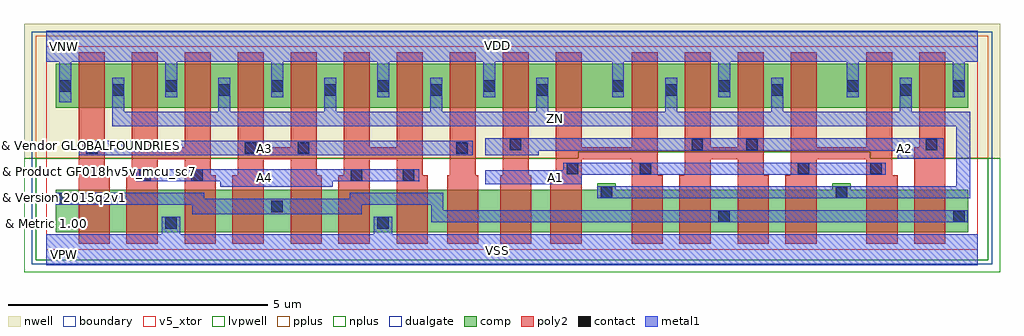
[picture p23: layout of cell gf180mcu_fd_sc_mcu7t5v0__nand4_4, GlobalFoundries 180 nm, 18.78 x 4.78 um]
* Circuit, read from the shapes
.subckt gf180mcu_fd_sc_mcu7t5v0__nand4_4 A1 A2 A3 A4 VDD VNW VSS ZN
XM1 n1 A3 n2 VSUBS nfet_05v0 w=0.82u l=0.6u
XM2 VSS A4 n1 VSUBS nfet_05v0 w=0.82u l=0.6u
XM3 n3 A4 VSS VSUBS nfet_05v0 w=0.82u l=0.6u
XM4 n2 A3 n3 VSUBS nfet_05v0 w=0.82u l=0.6u
XM5 n4 A3 n2 VSUBS nfet_05v0 w=0.82u l=0.6u
XM6 VSS A4 n4 VSUBS nfet_05v0 w=0.82u l=0.6u
XM7 n5 A4 VSS VSUBS nfet_05v0 w=0.82u l=0.6u
XM8 n6 A3 n5 VSUBS nfet_05v0 w=0.82u l=0.6u
XM9 n7 A2 n6 VSUBS nfet_05v0 w=0.82u l=0.6u
XM10 ZN A1 n7 VSUBS nfet_05v0 w=0.82u l=0.6u
XM11 n8 A1 ZN VSUBS nfet_05v0 w=0.82u l=0.6u
XM12 n2 A2 n8 VSUBS nfet_05v0 w=0.82u l=0.6u
XM13 n9 A2 n2 VSUBS nfet_05v0 w=0.82u l=0.6u
XM14 ZN A1 n9 VSUBS nfet_05v0 w=0.82u l=0.6u
XM15 n10 A1 ZN VSUBS nfet_05v0 w=0.82u l=0.6u
XM16 n2 A2 n10 VSUBS nfet_05v0 w=0.82u l=0.6u
XM17 ZN A3 VDD VNW pfet_05v0 w=0.845u l=0.5u m=4
XM18 VDD A4 ZN VNW pfet_05v0 w=0.845u l=0.5u m=4
XM19 ZN A2 VDD VNW pfet_05v0 w=0.845u l=0.5u m=4
XM20 VDD A1 ZN VNW pfet_05v0 w=0.845u l=0.5u m=4
.ends

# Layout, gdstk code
import gdstk
lib = gdstk.Library(unit=1e-6, precision=1e-09)
def R(c, l, rs):  # rectangles x0, y0, x1, y1
    for r in rs: c.add(gdstk.rectangle(r[:2], r[2:], *l))
def A(c, l, x, y, w, h, nx, ny, dx, dy):  # array of equal rectangles
    R(c, l, [(x+i*dx, y+j*dy, x+i*dx+w, y+j*dy+h) for i in range(nx) for j in range(ny)])
def P(c, l, *ps):  # polygons
    for p in ps: c.add(gdstk.Polygon(p, *l))
boundary = (0, 0)
nwell = (21, 0)
comp = (22, 0)
poly2 = (30, 0)
pplus = (31, 0)
nplus = (32, 0)
contact = (33, 0)
metal1 = (34, 0)
dualgate = (55, 0)
v5_xtor = (112, 1)
lvpwell = (204, 0)

gf180mcu_fd_sc_mcu7t5v0_ = lib.new_cell('gf180mcu_fd_sc_mcu7t5v0__nand4_4')
R(gf180mcu_fd_sc_mcu7t5v0_, boundary, [(0,0,17.92,3.92)])
P(gf180mcu_fd_sc_mcu7t5v0_, nwell, [(-0.43,1.76),(-0.43,4.35),(18.35,4.35),(18.35,1.76),(15.85,1.76),(15.85,1.885),(10.23,1.885),(10.23,1.76)])
R(gf180mcu_fd_sc_mcu7t5v0_, comp, [(0.18,2.735,17.74,3.58)])
P(gf180mcu_fd_sc_mcu7t5v0_, comp, [(0.18,0.34),(0.18,1.16),(10.6,1.16),(10.6,1.285),(10.96,1.285),(10.96,1.16),(15.12,1.16),(15.12,1.285),(15.48,1.285),(15.48,1.16),(17.74,1.16),(17.74,0.34)])
P(gf180mcu_fd_sc_mcu7t5v0_, poly2, [(0.62,0.12),(0.62,3.8),(1.12,3.8),(1.12,1.44),(1.22,1.44),(1.22,0.12)],
  [(1.54,0.12),(1.54,1.44),(1.64,1.44),(1.64,3.8),(2.14,3.8),(2.14,1.97),(2.66,1.97),(2.66,3.8),(3.16,3.8),(3.16,1.44),(3.26,1.44),(3.26,0.12),(2.66,0.12),(2.66,1.74),(2.14,1.74),(2.14,0.12)],
  [(3.58,0.12),(3.58,1.44),(3.68,1.44),(3.68,3.8),(4.18,3.8),(4.18,1.97),(4.7,1.97),(4.7,3.8),(5.2,3.8),(5.2,1.44),(5.3,1.44),(5.3,0.12),(4.7,0.12),(4.7,1.74),(4.18,1.74),(4.18,0.12)],
  [(5.62,0.12),(5.62,1.44),(5.72,1.44),(5.72,3.8),(6.22,3.8),(6.22,1.97),(6.74,1.97),(6.74,3.8),(7.24,3.8),(7.24,1.44),(7.34,1.44),(7.34,0.12),(6.74,0.12),(6.74,1.74),(6.22,1.74),(6.22,0.12)],
  [(7.71,0.12),(7.71,1.44),(7.76,1.44),(7.76,3.8),(8.26,3.8),(8.26,1.44),(8.31,1.44),(8.31,0.12)],
  [(8.73,0.12),(8.73,1.44),(8.78,1.44),(8.78,3.8),(9.28,3.8),(9.28,1.44),(9.33,1.44),(9.33,0.12)],
  [(9.7,0.12),(9.7,1.44),(9.8,1.44),(9.8,3.8),(10.3,3.8),(10.3,1.97),(11.26,1.97),(11.26,3.8),(11.76,3.8),(11.76,1.44),(11.86,1.44),(11.86,0.12),(11.26,0.12),(11.26,1.74),(10.3,1.74),(10.3,0.12)],
  [(12.18,0.12),(12.18,1.44),(12.28,1.44),(12.28,3.8),(12.78,3.8),(12.78,1.97),(13.3,1.97),(13.3,3.8),(13.8,3.8),(13.8,1.44),(13.9,1.44),(13.9,0.12),(13.3,0.12),(13.3,1.74),(12.78,1.74),(12.78,0.12)],
  [(14.22,0.12),(14.22,1.44),(14.32,1.44),(14.32,3.8),(14.82,3.8),(14.82,1.97),(15.78,1.97),(15.78,3.8),(16.28,3.8),(16.28,1.44),(16.38,1.44),(16.38,0.12),(15.78,0.12),(15.78,1.74),(14.82,1.74),(14.82,0.12)],
  [(16.7,0.12),(16.7,1.97),(16.8,1.97),(16.8,3.8),(17.3,3.8),(17.3,0.12)])
P(gf180mcu_fd_sc_mcu7t5v0_, pplus, [(-0.2,1.76),(-0.2,4.12),(18.12,4.12),(18.12,1.76),(15.85,1.76),(15.85,1.885),(10.23,1.885),(10.23,1.76)])
P(gf180mcu_fd_sc_mcu7t5v0_, nplus, [(-0.2,-0.2),(-0.2,1.76),(10.23,1.76),(10.23,1.885),(15.85,1.885),(15.85,1.76),(18.12,1.76),(18.12,-0.2)])
A(gf180mcu_fd_sc_mcu7t5v0_, contact, 1.27, 2.97, 0.22, 0.22, 5, 1, 2.04, 0)
A(gf180mcu_fd_sc_mcu7t5v0_, contact, 0.25, 3.045, 0.22, 0.22, 5, 1, 2.04, 0)
R(gf180mcu_fd_sc_mcu7t5v0_, contact, [(2.29,0.41,2.51,0.63), (6.37,0.41,6.59,0.63), (12.93,0.535,13.15,0.755), (17.45,0.535,17.67,0.755), (4.33,0.725,4.55,0.945), (0.25,0.87,0.47,1.09), (10.67,0.995,10.89,1.215), (15.19,0.995,15.41,1.215), (1.79,1.33,2.01,1.55), (2.79,1.33,3.01,1.55), (5.855,1.33,6.075,1.55), (6.86,1.33,7.08,1.55), (10.01,1.455,10.23,1.675), (11.415,1.455,11.635,1.675), (14.455,1.455,14.675,1.675), (15.85,1.455,16.07,1.675), (0.77,1.85,0.99,2.07), (3.82,1.85,4.04,2.07), (4.835,1.85,5.055,2.07), (7.89,1.85,8.11,2.07), (8.92,1.915,9.14,2.135), (12.415,1.915,12.635,2.135), (13.465,1.915,13.685,2.135), (16.925,1.915,17.145,2.135), (11.91,2.97,12.13,3.19), (13.95,2.97,14.17,3.19), (16.43,2.97,16.65,3.19), (10.89,3.045,11.11,3.265), (12.93,3.045,13.15,3.265), (15.41,3.045,15.63,3.265), (17.45,3.045,17.67,3.265)])
R(gf180mcu_fd_sc_mcu7t5v0_, metal1, [(0.62,1.825,8.2,2.095)])
P(gf180mcu_fd_sc_mcu7t5v0_, metal1, [(3.345,1.21),(3.345,1.325),(1.73,1.325),(1.73,1.555),(7.18,1.555),(7.18,1.325),(5.51,1.325),(5.51,1.21)],
  [(8.45,1.265),(8.45,1.535),(9.95,1.535),(9.95,1.68),(16.155,1.68),(16.155,1.45),(10.3,1.45),(10.3,1.265)],
  [(16.385,1.75),(16.385,1.91),(9.47,1.91),(9.47,1.825),(8.45,1.825),(8.45,2.15),(17.27,2.15),(17.27,1.75)],
  [(7.405,0.53),(7.405,0.865),(6.07,0.865),(6.07,0.69),(2.81,0.69),(2.81,0.865),(0.18,0.865),(0.18,1.095),(3.04,1.095),(3.04,0.98),(5.84,0.98),(5.84,1.095),(7.635,1.095),(7.635,0.76),(17.73,0.76),(17.73,0.53)],
  [(10.6,0.99),(10.6,1.22),(17.505,1.22),(17.505,2.38),(1.265,2.38),(1.265,3.31),(1.495,3.31),(1.495,2.655),(3.305,2.655),(3.305,3.31),(3.535,3.31),(3.535,2.655),(5.345,2.655),(5.345,3.31),(5.575,3.31),(5.575,2.655),(7.385,2.655),(7.385,3.31),(7.615,3.31),(7.615,2.655),(9.425,2.655),(9.425,3.31),(9.655,3.31),(9.655,2.655),(11.905,2.655),(11.905,3.31),(12.135,3.31),(12.135,2.655),(13.945,2.655),(13.945,3.31),(14.175,3.31),(14.175,2.655),(16.425,2.655),(16.425,3.31),(16.655,3.31),(16.655,2.655),(17.775,2.655),(17.775,0.99)],
  [(0,-0.3),(0,0.3),(2.22,0.3),(2.22,0.635),(2.58,0.635),(2.58,0.3),(6.3,0.3),(6.3,0.635),(6.66,0.635),(6.66,0.3),(17.92,0.3),(17.92,-0.3)],
  [(0.245,2.84),(0.245,3.62),(0,3.62),(0,4.22),(17.92,4.22),(17.92,3.62),(17.675,3.62),(17.675,2.935),(17.445,2.935),(17.445,3.62),(15.635,3.62),(15.635,2.935),(15.405,2.935),(15.405,3.62),(13.155,3.62),(13.155,2.935),(12.925,2.935),(12.925,3.62),(11.115,3.62),(11.115,2.935),(10.885,2.935),(10.885,3.62),(8.635,3.62),(8.635,2.935),(8.405,2.935),(8.405,3.62),(6.595,3.62),(6.595,2.935),(6.365,2.935),(6.365,3.62),(4.555,3.62),(4.555,2.935),(4.325,2.935),(4.325,3.62),(2.515,3.62),(2.515,2.935),(2.285,2.935),(2.285,3.62),(0.475,3.62),(0.475,2.84)])
R(gf180mcu_fd_sc_mcu7t5v0_, dualgate, [(-0.28,-0.28,18.2,4.2)])
R(gf180mcu_fd_sc_mcu7t5v0_, v5_xtor, [(0,0,17.92,3.92)])
P(gf180mcu_fd_sc_mcu7t5v0_, lvpwell, [(-0.43,-0.43),(-0.43,1.76),(10.23,1.76),(10.23,1.885),(15.85,1.885),(15.85,1.76),(18.35,1.76),(18.35,-0.43)])
gf180mcu_fd_sc_mcu7t5v0_.add(gdstk.Label('A3', (4.2,1.96), layer=34, texttype=10))
gf180mcu_fd_sc_mcu7t5v0_.add(gdstk.Label('A4', (4.2,1.4), layer=34, texttype=10))
gf180mcu_fd_sc_mcu7t5v0_.add(gdstk.Label('VDD', (8.68,3.94), layer=34, texttype=10))
gf180mcu_fd_sc_mcu7t5v0_.add(gdstk.Label('VSS', (8.68,-0.02), layer=34, texttype=10))
gf180mcu_fd_sc_mcu7t5v0_.add(gdstk.Label('ZN', (9.8,2.52), layer=34, texttype=10))
gf180mcu_fd_sc_mcu7t5v0_.add(gdstk.Label('A1', (9.8,1.4), layer=34, texttype=10))
gf180mcu_fd_sc_mcu7t5v0_.add(gdstk.Label('A2', (16.52,1.96), layer=34, texttype=10))
gf180mcu_fd_sc_mcu7t5v0_.add(gdstk.Label('& Vendor GLOBALFOUNDRIES', (0,2), layer=63, texttype=63))
gf180mcu_fd_sc_mcu7t5v0_.add(gdstk.Label('& Product GF018hv5v_mcu_sc7', (0,1.5), layer=63, texttype=63))
gf180mcu_fd_sc_mcu7t5v0_.add(gdstk.Label('& Version 2015q2v1', (0,1), layer=63, texttype=63))
gf180mcu_fd_sc_mcu7t5v0_.add(gdstk.Label('& Metric 1.00', (0,0.5), layer=63, texttype=63))
gf180mcu_fd_sc_mcu7t5v0_.add(gdstk.Label('VNW', (0.345,3.92), layer=21, texttype=10))
gf180mcu_fd_sc_mcu7t5v0_.add(gdstk.Label('VPW', (0.34,-0.085), layer=204, texttype=10))

lib.write_gds('gf180mcu_fd_sc_mcu7t5v0__nand4_4.gds')
